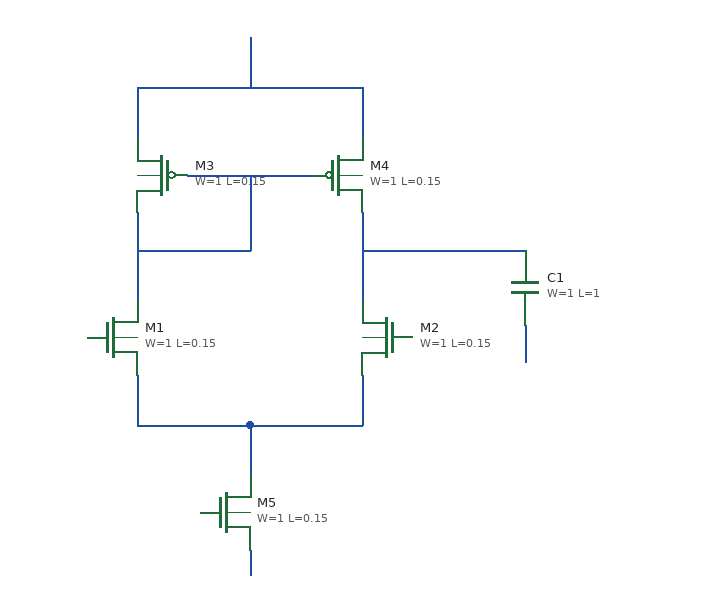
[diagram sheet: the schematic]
v {xschem version=3.4.7 file_version=1.2}
G {}
K {}
V {}
S {}
E {}
N -50 -360 50 -360 {lab=#net1}
N -90 -330 -90 -260 {lab=#net1}
N -0 -360 0 -300 {lab=#net1}
N -90 -300 -0 -300 {lab=#net1}
N 90 -330 90 -260 {lab=#net2}
N -90 -200 -90 -160 {lab=#net3}
N -90 -160 -0 -160 {lab=#net3}
N 90 -200 90 -160 {lab=#net3}
N -0 -160 90 -160 {lab=#net3}
N 0 -160 -0 -120 {lab=#net3}
N -90 -430 -90 -390 {lab=#net4}
N 90 -430 90 -390 {lab=#net4}
N -90 -430 90 -430 {lab=#net4}
N 0 -470 0 -430 {lab=#net4}
N 90 -300 220 -300 {lab=#net2}
N 220 -240 220 -210 {lab=#net5}
N 0 -60 -0 -40 {lab=#net6}
C {sky130_fd_pr/nfet_01v8.sym} -110 -230 0 0 {name=M1
L=0.15
W=1
nf=1 
mult=1
ad="'int((nf+1)/2) * W/nf * 0.29'" 
pd="'2*int((nf+1)/2) * (W/nf + 0.29)'"
as="'int((nf+2)/2) * W/nf * 0.29'" 
ps="'2*int((nf+2)/2) * (W/nf + 0.29)'"
nrd="'0.29 / W'" nrs="'0.29 / W'"
sa=0 sb=0 sd=0
model=nfet_01v8
spiceprefix=X
}
C {sky130_fd_pr/nfet_01v8.sym} 110 -230 0 1 {name=M2
L=0.15
W=1
nf=1 
mult=1
ad="'int((nf+1)/2) * W/nf * 0.29'" 
pd="'2*int((nf+1)/2) * (W/nf + 0.29)'"
as="'int((nf+2)/2) * W/nf * 0.29'" 
ps="'2*int((nf+2)/2) * (W/nf + 0.29)'"
nrd="'0.29 / W'" nrs="'0.29 / W'"
sa=0 sb=0 sd=0
model=nfet_01v8
spiceprefix=X
}
C {sky130_fd_pr/pfet_01v8.sym} -70 -360 0 1 {name=M3
L=0.15
W=1
nf=1
mult=1
ad="'int((nf+1)/2) * W/nf * 0.29'" 
pd="'2*int((nf+1)/2) * (W/nf + 0.29)'"
as="'int((nf+2)/2) * W/nf * 0.29'" 
ps="'2*int((nf+2)/2) * (W/nf + 0.29)'"
nrd="'0.29 / W'" nrs="'0.29 / W'"
sa=0 sb=0 sd=0
model=pfet_01v8
spiceprefix=X
}
C {sky130_fd_pr/pfet_01v8.sym} 70 -360 0 0 {name=M4
L=0.15
W=1
nf=1
mult=1
ad="'int((nf+1)/2) * W/nf * 0.29'" 
pd="'2*int((nf+1)/2) * (W/nf + 0.29)'"
as="'int((nf+2)/2) * W/nf * 0.29'" 
ps="'2*int((nf+2)/2) * (W/nf + 0.29)'"
nrd="'0.29 / W'" nrs="'0.29 / W'"
sa=0 sb=0 sd=0
model=pfet_01v8
spiceprefix=X
}
C {sky130_fd_pr/nfet_01v8.sym} -20 -90 0 0 {name=M5
L=0.15
W=1
nf=1 
mult=1
ad="'int((nf+1)/2) * W/nf * 0.29'" 
pd="'2*int((nf+1)/2) * (W/nf + 0.29)'"
as="'int((nf+2)/2) * W/nf * 0.29'" 
ps="'2*int((nf+2)/2) * (W/nf + 0.29)'"
nrd="'0.29 / W'" nrs="'0.29 / W'"
sa=0 sb=0 sd=0
model=nfet_01v8
spiceprefix=X
}
C {sky130_fd_pr/cap_mim_m3_1.sym} 220 -270 0 0 {name=C1 model=cap_mim_m3_1 W=1 L=1 MF=1 spiceprefix=X}
